VERSION 5.8 ;
BUSBITCHARS "[]" ;
DIVIDERCHAR "/" ;

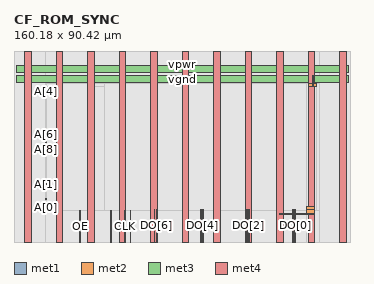
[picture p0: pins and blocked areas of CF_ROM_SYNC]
MACRO CF_ROM_SYNC
  CLASS BLOCK ;
  ORIGIN 0 0 ;
  FOREIGN CF_ROM_SYNC 0 0 ;
  SIZE 160.18 BY 90.42 ;
  PIN DO[0]
    DIRECTION OUTPUT ;
    USE SIGNAL ;
    PORT
      LAYER met1 ;
        RECT 133.68 0 133.875 15.38 ;
    END
  END DO[0]
  PIN DO[1]
    DIRECTION OUTPUT ;
    USE SIGNAL ;
    PORT
      LAYER met1 ;
        RECT 132.715 0 132.91 15.38 ;
    END
  END DO[1]
  PIN DO[2]
    DIRECTION OUTPUT ;
    USE SIGNAL ;
    PORT
      LAYER met1 ;
        RECT 111.73 0 111.925 15.38 ;
    END
  END DO[2]
  PIN DO[3]
    DIRECTION OUTPUT ;
    USE SIGNAL ;
    PORT
      LAYER met1 ;
        RECT 110.765 0 110.96 15.38 ;
    END
  END DO[3]
  PIN DO[4]
    DIRECTION OUTPUT ;
    USE SIGNAL ;
    PORT
      LAYER met1 ;
        RECT 89.78 0 89.975 15.38 ;
    END
  END DO[4]
  PIN DO[6]
    DIRECTION OUTPUT ;
    USE SIGNAL ;
    PORT
      LAYER met1 ;
        RECT 67.83 0 68.025 15.38 ;
    END
  END DO[6]
  PIN A[2]
    DIRECTION INPUT ;
    USE SIGNAL ;
    PORT
      LAYER met2 ;
        RECT 15.01 25.73 15.4 26.215 ;
    END
  END A[2]
  PIN A[1]
    DIRECTION INPUT ;
    USE SIGNAL ;
    PORT
      LAYER met2 ;
        RECT 15.01 27.13 15.4 27.615 ;
    END
  END A[1]
  PIN A[0]
    DIRECTION INPUT ;
    USE SIGNAL ;
    PORT
      LAYER met2 ;
        RECT 15.015 16.285 15.405 16.77 ;
    END
  END A[0]
  PIN A[3]
    DIRECTION INPUT ;
    USE SIGNAL ;
    PORT
      LAYER met2 ;
        RECT 15.02 20.125 15.41 20.61 ;
    END
  END A[3]
  PIN A[9]
    DIRECTION INPUT ;
    USE SIGNAL ;
    PORT
      LAYER met2 ;
        RECT 15.01 48.79 15.4 49.275 ;
    END
  END A[9]
  PIN A[8]
    DIRECTION INPUT ;
    USE SIGNAL ;
    PORT
      LAYER met2 ;
        RECT 15.01 47.39 15.4 47.875 ;
    END
  END A[8]
  PIN DO[5]
    DIRECTION OUTPUT ;
    USE SIGNAL ;
    PORT
      LAYER met1 ;
        RECT 88.815 0 89.01 15.38 ;
    END
  END DO[5]
  PIN vpwr
    DIRECTION INPUT ;
    USE POWER ;
    PORT
      LAYER met2 ;
        RECT 139.185 15.41 143.01 16.725 ;
        RECT 139.185 13.24 143.01 16.725 ;
      LAYER met3 ;
        RECT 126.31 13.24 143.01 13.72 ;
        RECT 1.23 80.72 158.95 83.82 ;
      LAYER met4 ;
        RECT 5 0 8.1 90.42 ;
        RECT 35 0 38.1 90.42 ;
        RECT 65 0 68.1 90.42 ;
        RECT 95 0 98.1 90.42 ;
        RECT 125 0 128.1 90.42 ;
        RECT 155 0 158.1 90.42 ;
    END
  END vpwr
  PIN vgnd
    DIRECTION INPUT ;
    USE GROUND ;
    PORT
      LAYER met2 ;
        RECT 140.215 73.965 144.04 75.28 ;
        RECT 141.89 73.965 142.37 79.02 ;
      LAYER met3 ;
        RECT 1.23 75.92 158.95 79.02 ;
      LAYER met4 ;
        RECT 20 0 23.1 90.42 ;
        RECT 50 0 53.1 90.42 ;
        RECT 80 0 83.1 90.42 ;
        RECT 110 0 113.1 90.42 ;
        RECT 140 0 143.1 90.42 ;
    END
  END vgnd
  PIN OE
    DIRECTION INPUT ;
    USE SIGNAL ;
    PORT
      LAYER met1 ;
        RECT 31.4 0 31.595 15.225 ;
    END
  END OE
  PIN EN
    DIRECTION INPUT ;
    USE SIGNAL ;
    PORT
      LAYER met1 ;
        RECT 55.23 0 55.425 15.225 ;
    END
  END EN
  PIN CLK
    DIRECTION INPUT ;
    USE SIGNAL ;
    PORT
      LAYER met1 ;
        RECT 52.535 0 52.73 15.225 ;
    END
  END CLK
  PIN RST
    DIRECTION INPUT ;
    USE SIGNAL ;
    PORT
      LAYER met1 ;
        RECT 46.085 0 46.28 15.225 ;
    END
  END RST
  PIN DO[7]
    DIRECTION OUTPUT ;
    USE SIGNAL ;
    PORT
      LAYER met1 ;
        RECT 66.865 0 67.06 15.38 ;
    END
  END DO[7]
  PIN A[5]
    DIRECTION INPUT ;
    USE SIGNAL ;
    PORT
      LAYER met2 ;
        RECT 15.01 72.7 15.4 73.185 ;
    END
  END A[5]
  PIN A[4]
    DIRECTION INPUT ;
    USE SIGNAL ;
    PORT
      LAYER met2 ;
        RECT 15.01 71.31 15.4 71.795 ;
    END
  END A[4]
  PIN A[6]
    DIRECTION INPUT ;
    USE SIGNAL ;
    PORT
      LAYER met2 ;
        RECT 15.01 51.03 15.4 51.515 ;
    END
  END A[6]
  PIN A[7]
    DIRECTION INPUT ;
    USE SIGNAL ;
    PORT
      LAYER met2 ;
        RECT 15.01 49.63 15.4 50.115 ;
    END
  END A[7]
  OBS
    # Generated by scripts/rom_abstract/make_rom_lef.py.
    # Wrap halo plus core li1/met1/met2 OBS at (+15, +15).
    # DO ports extend to y=0; signal pins and DO corridors cut out.
    LAYER li1 ;
      RECT 0 0 160.18 90.42 ;
      RECT 15 15 145.18 75.42 ;
    LAYER met1 ;
      RECT 0 0 15 90.42 ;
      RECT 15 0 31.4 15 ;
      RECT 31.595 0 46.085 15 ;
      RECT 46.28 0 52.535 15 ;
      RECT 52.73 0 55.23 15 ;
      RECT 55.425 0 66.585 15 ;
      RECT 67.34 0 67.55 15 ;
      RECT 68.305 0 88.535 15 ;
      RECT 89.29 0 89.5 15 ;
      RECT 90.255 0 110.485 15 ;
      RECT 111.24 0 111.45 15 ;
      RECT 112.205 0 132.435 15 ;
      RECT 133.19 0 133.4 15 ;
      RECT 134.155 0 145.18 15 ;
      RECT 145.18 0 160.18 90.42 ;
      RECT 15 15 31.4 75.42 ;
      RECT 31.595 15 46.085 75.42 ;
      RECT 46.28 15 52.535 75.42 ;
      RECT 52.73 15 55.23 75.42 ;
      RECT 55.425 15 66.585 15.38 ;
      RECT 67.34 15 67.55 15.38 ;
      RECT 68.305 15 88.535 15.38 ;
      RECT 89.29 15 89.5 15.38 ;
      RECT 90.255 15 110.485 15.38 ;
      RECT 111.24 15 111.45 15.38 ;
      RECT 112.205 15 132.435 15.38 ;
      RECT 133.19 15 133.4 15.38 ;
      RECT 134.155 15 145.18 15.38 ;
      RECT 31.4 15.225 31.595 75.42 ;
      RECT 46.085 15.225 46.28 75.42 ;
      RECT 52.535 15.225 52.73 75.42 ;
      RECT 55.23 15.225 55.425 75.42 ;
      RECT 55.425 15.38 66.865 75.42 ;
      RECT 66.865 15.38 67.06 75.42 ;
      RECT 67.06 15.38 67.83 75.42 ;
      RECT 67.83 15.38 68.025 75.42 ;
      RECT 68.025 15.38 88.815 75.42 ;
      RECT 88.815 15.38 89.01 75.42 ;
      RECT 89.01 15.38 89.78 75.42 ;
      RECT 89.78 15.38 89.975 75.42 ;
      RECT 89.975 15.38 110.765 75.42 ;
      RECT 110.765 15.38 110.96 75.42 ;
      RECT 110.96 15.38 111.73 75.42 ;
      RECT 111.73 15.38 111.925 75.42 ;
      RECT 111.925 15.38 132.715 75.42 ;
      RECT 132.715 15.38 132.91 75.42 ;
      RECT 132.91 15.38 133.68 75.42 ;
      RECT 133.68 15.38 133.875 75.42 ;
      RECT 133.875 15.38 145.18 75.42 ;
      RECT 15 75.42 145.18 90.42 ;
    LAYER met2 ;
      RECT 0 0 15 90.42 ;
      RECT 15 0 139.185 15 ;
      RECT 139.185 0 143.01 13.24 ;
      RECT 143.01 0 145.18 15 ;
      RECT 145.18 0 160.18 90.42 ;
      RECT 15 15 15.14 16.285 ;
      RECT 15.14 15 15.145 16.285 ;
      RECT 15.145 15 15.15 16.285 ;
      RECT 15.15 15 15.27 16.285 ;
      RECT 15.27 15 15.275 16.285 ;
      RECT 15.275 15 15.28 16.285 ;
      RECT 15.28 15 15.61 16.285 ;
      RECT 15.61 15 20.3 73.82 ;
      RECT 20.3 15 37.925 75.42 ;
      RECT 37.925 15 43.26 74 ;
      RECT 43.26 15 139.185 75.42 ;
      RECT 139.185 15 140.215 15.41 ;
      RECT 140.215 15 143.01 15.41 ;
      RECT 143.01 15 144.04 73.965 ;
      RECT 144.04 15 145.18 75.42 ;
      RECT 15 16.285 15.015 16.77 ;
      RECT 15.405 16.285 15.61 16.77 ;
      RECT 139.185 16.725 140.215 75.42 ;
      RECT 140.215 16.725 143.01 73.965 ;
      RECT 15 16.77 15.14 20.125 ;
      RECT 15.14 16.77 15.145 20.125 ;
      RECT 15.145 16.77 15.15 20.125 ;
      RECT 15.15 16.77 15.27 20.125 ;
      RECT 15.27 16.77 15.275 20.125 ;
      RECT 15.275 16.77 15.28 20.125 ;
      RECT 15.28 16.77 15.61 20.125 ;
      RECT 15 20.125 15.02 20.61 ;
      RECT 15.41 20.125 15.61 20.61 ;
      RECT 15 20.61 15.14 25.73 ;
      RECT 15.14 20.61 15.145 25.73 ;
      RECT 15.145 20.61 15.15 25.73 ;
      RECT 15.15 20.61 15.27 25.73 ;
      RECT 15.27 20.61 15.275 25.73 ;
      RECT 15.275 20.61 15.28 25.73 ;
      RECT 15.28 20.61 15.61 25.73 ;
      RECT 15 25.73 15.01 26.215 ;
      RECT 15.4 25.73 15.61 26.215 ;
      RECT 15 26.215 15.14 27.13 ;
      RECT 15.14 26.215 15.145 27.13 ;
      RECT 15.145 26.215 15.15 27.13 ;
      RECT 15.15 26.215 15.27 27.13 ;
      RECT 15.27 26.215 15.275 27.13 ;
      RECT 15.275 26.215 15.28 27.13 ;
      RECT 15.28 26.215 15.61 27.13 ;
      RECT 15 27.13 15.01 27.615 ;
      RECT 15.4 27.13 15.61 27.615 ;
      RECT 15 27.615 15.14 47.39 ;
      RECT 15.14 27.615 15.145 47.39 ;
      RECT 15.145 27.615 15.15 47.39 ;
      RECT 15.15 27.615 15.27 47.39 ;
      RECT 15.27 27.615 15.275 47.39 ;
      RECT 15.275 27.615 15.28 47.39 ;
      RECT 15.28 27.615 15.61 47.39 ;
      RECT 15 47.39 15.01 47.875 ;
      RECT 15.4 47.39 15.61 47.875 ;
      RECT 15 47.875 15.14 48.79 ;
      RECT 15.14 47.875 15.145 48.79 ;
      RECT 15.145 47.875 15.15 48.79 ;
      RECT 15.15 47.875 15.27 48.79 ;
      RECT 15.27 47.875 15.275 48.79 ;
      RECT 15.275 47.875 15.28 48.79 ;
      RECT 15.28 47.875 15.61 48.79 ;
      RECT 15 48.79 15.01 49.275 ;
      RECT 15.4 48.79 15.61 49.275 ;
      RECT 15 49.275 15.14 49.63 ;
      RECT 15.14 49.275 15.145 49.63 ;
      RECT 15.145 49.275 15.15 49.63 ;
      RECT 15.15 49.275 15.27 49.63 ;
      RECT 15.27 49.275 15.275 49.63 ;
      RECT 15.275 49.275 15.28 49.63 ;
      RECT 15.28 49.275 15.61 49.63 ;
      RECT 15 49.63 15.01 50.115 ;
      RECT 15.4 49.63 15.61 50.115 ;
      RECT 15 50.115 15.14 51.03 ;
      RECT 15.14 50.115 15.145 51.03 ;
      RECT 15.145 50.115 15.15 51.03 ;
      RECT 15.15 50.115 15.27 51.03 ;
      RECT 15.27 50.115 15.275 51.03 ;
      RECT 15.275 50.115 15.28 51.03 ;
      RECT 15.28 50.115 15.61 51.03 ;
      RECT 15 51.03 15.01 51.515 ;
      RECT 15.4 51.03 15.61 51.515 ;
      RECT 15 51.515 15.14 71.31 ;
      RECT 15.14 51.515 15.145 71.31 ;
      RECT 15.145 51.515 15.15 71.31 ;
      RECT 15.15 51.515 15.27 71.31 ;
      RECT 15.27 51.515 15.275 71.31 ;
      RECT 15.275 51.515 15.28 71.31 ;
      RECT 15.28 51.515 15.61 71.31 ;
      RECT 15 71.31 15.01 71.795 ;
      RECT 15.4 71.31 15.61 71.795 ;
      RECT 15 71.795 15.14 72.7 ;
      RECT 15.14 71.795 15.145 72.7 ;
      RECT 15.145 71.795 15.15 72.7 ;
      RECT 15.15 71.795 15.27 72.7 ;
      RECT 15.27 71.795 15.275 72.7 ;
      RECT 15.275 71.795 15.28 72.7 ;
      RECT 15.28 71.795 15.61 72.7 ;
      RECT 15 72.7 15.01 73.185 ;
      RECT 15.4 72.7 15.61 73.185 ;
      RECT 15 73.185 15.14 75.42 ;
      RECT 15.14 73.185 15.145 75.42 ;
      RECT 15.145 73.185 15.15 75.42 ;
      RECT 15.15 73.185 15.27 75.42 ;
      RECT 15.27 73.185 15.275 75.42 ;
      RECT 15.275 73.185 15.28 75.42 ;
      RECT 15.28 73.185 15.61 75.42 ;
      RECT 37.925 75.23 43.26 75.42 ;
      RECT 15.61 75.25 20.3 75.42 ;
      RECT 140.215 75.28 143.01 75.42 ;
      RECT 143.01 75.28 144.04 75.42 ;
      RECT 15 75.42 141.89 90.42 ;
      RECT 142.37 75.42 145.18 90.42 ;
      RECT 141.89 79.02 142.37 90.42 ;
  END
END CF_ROM_SYNC

END LIBRARY
